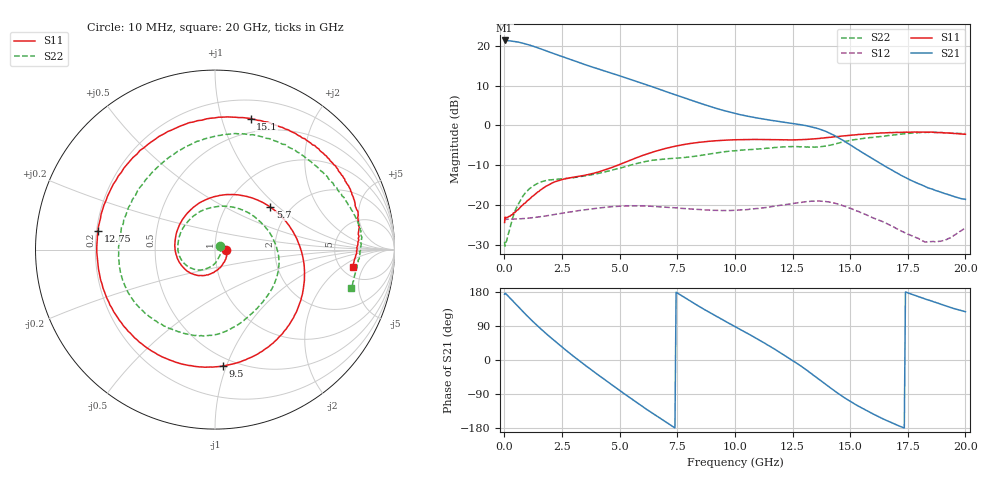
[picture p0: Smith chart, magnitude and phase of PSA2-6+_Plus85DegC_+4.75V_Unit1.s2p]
!Keysight Technologies,N5242A,MY47200155,A.10.49.08
!Date: Thursday, October 19, 2023 15:40:47
!Correction: S11(Full 2 Port(1,2))
!S21(Full 2 Port(1,2))
!S12(Full 2 Port(1,2))
!S22(Full 2 Port(1,2))
!S2P File: Measurements: S11, S21, S12, S22:
# Hz S  dB  R 50
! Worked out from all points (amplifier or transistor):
!   408 points, 10 MHz to 20 GHz, reference 50 ohm
!   highest |S21| = 21.3 dB at 10 MHz (marker M1)
!   |S21| within 3 dB of that: start of sweep to 2 GHz
!   unconditionally stable (mu >= 1): start of sweep to end of sweep
!   at 3.05 GHz: K = 1.06, MAG = 17.4 dB, |S12| = -21.6 dB
!   at 9.85 GHz: K = 1.62, MAG = 7.7 dB, |S12| = -21.4 dB
!   at 20 GHz: K = 12.41, MAG = -10.3 dB, |S12| = -25.9 dB
!   S11 on the Smith chart (normalised r, x): 10 MHz: 1.13, -0.00; 5.7 GHz: 1.59, +0.89; 9.5 GHz: 0.43, -0.97; 12.75 GHz: 0.21, +0.07; 15.1 GHz: 0.36, +1.24; 20 GHz: 6.34, -3.03
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1e7  -24.38 -1.0  21.33 173.7  -23.55 -4.9  -29.24 34.0
6e7  -23.22 -6.0  21.28 175.0  -23.60 -2.2  -29.58 -17.0
3.5e8  -22.41 -35.4  21.15 156.5  -23.54 -6.0  -23.46 -83.4
7.5e8  -20.21 -67.5  20.71 131.0  -23.44 -12.5  -18.25 -116.8
1e9  -18.89 -82.5  20.32 115.7  -23.32 -16.9  -16.42 -132.0
1.3e9  -17.46 -98.3  19.78 97.9  -23.11 -22.1  -15.01 -148.1
1.8e9  -15.31 -122.6  18.74 70.2  -22.73 -31.5  -13.84 -172.5
2.3e9  -13.97 -147.4  17.70 44.3  -22.26 -41.8  -13.52 162.2
2.8e9  -13.21 -172.6  16.66 19.4  -21.79 -53.3  -13.26 136.0
3.35e9  -12.69 159.4  15.55 -6.7  -21.31 -66.7  -12.82 108.5
3.9e9  -11.99 130.8  14.48 -31.8  -20.89 -81.0  -12.29 83.2
4.45e9  -10.99 101.1  13.47 -56.2  -20.54 -95.7  -11.54 59.3
5.7e9  -8.20 37.5  11.13 -110.5  -20.20 -131.2  -9.64 10.2
6.7e9  -6.24 -3.5  9.13 -151.7  -20.42 -158.8  -8.58 -19.4
8.1e9  -4.52 -48.2  6.32 154.2  -21.01 165.5  -7.88 -55.3
9.5e9  -3.74 -86.0  3.76 105.0  -21.37 134.1  -6.65 -84.9
1.005e10  -3.60 -100.1  2.94 86.7  -21.30 122.8  -6.34 -95.8
1.275e10  -3.62 171.1  0.25 -11.2  -19.41 53.8  -5.34 -170.0
1.335e10  -3.44 144.9  -0.40 -37.2  -19.05 33.2  -5.50 164.1
1.51e10  -2.42 74.8  -5.24 -112.6  -21.03 -30.8  -3.66 80.1
1.67e10  -1.84 39.3  -10.86 -162.8  -24.97 -73.4  -2.55 31.9
2e10  -2.24 -7.1  -18.57 127.5  -25.88 -97.5  -2.08 -15.9
